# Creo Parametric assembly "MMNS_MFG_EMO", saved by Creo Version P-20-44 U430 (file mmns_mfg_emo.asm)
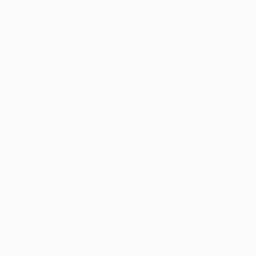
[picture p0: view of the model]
Units: millimeter Newton Second (mmNs); MM, TONNE, SECS

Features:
  1. datum plane "EMO_RIGHT"
  2. datum plane "EMO_TOP"
  3. datum plane "EMO_FRONT"
  4. coordinate system

Other named items: EMO_DEF_CSYS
